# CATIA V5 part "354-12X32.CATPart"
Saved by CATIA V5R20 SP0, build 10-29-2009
Part number: 354-12X32
Definition: NONE
Nomenclature: 354-12X32
Source: Unknown
Description: 354-12X32
Bounding box of the stored display mesh (mm): x -16 to 16, y -11 to 11, z -11 to 11
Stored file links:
  C:\Users\Utente\Desktop\IO LAVORO\3D X SITO CF\X SITO\PLASTICA\354\354-12X32.CATPart

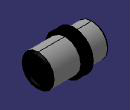
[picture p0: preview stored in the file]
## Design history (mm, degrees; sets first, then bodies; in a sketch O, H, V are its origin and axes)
Body1 "354-12X32" (main body)
  Solid1: solid without history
